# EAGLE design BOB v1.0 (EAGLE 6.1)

## Sheet 1 of 2: Pi Cam Daughterboard

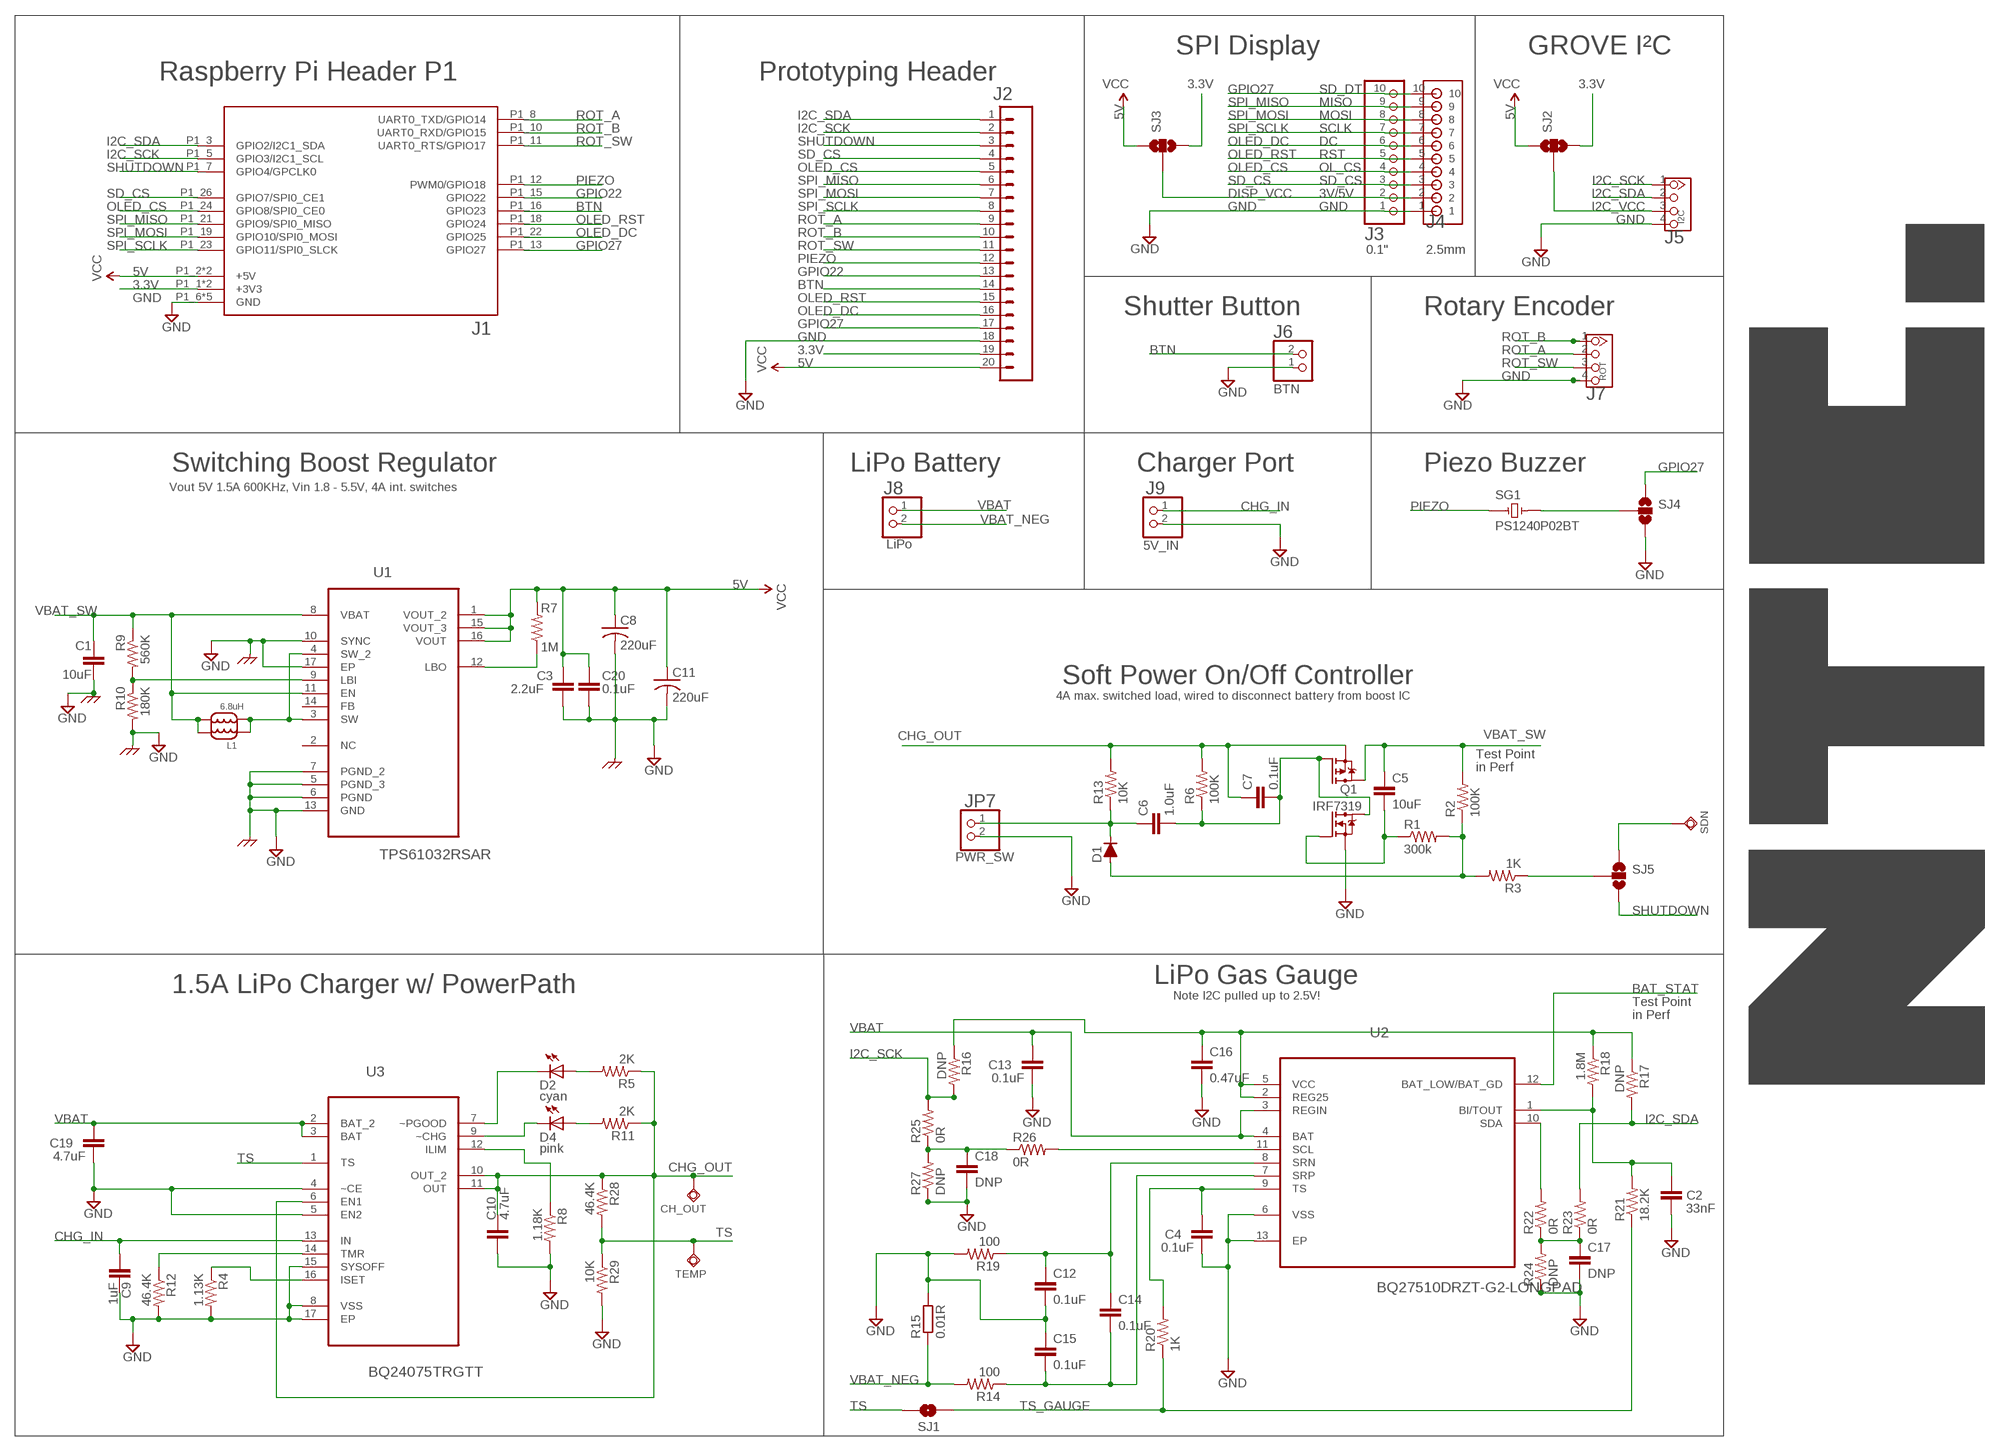
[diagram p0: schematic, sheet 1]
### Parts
C1  10uF  CAP1206  [1206]
C2  33nF  CAP0603-CAP  [0603-CAP]
C3  2.2uF  CAP0603  [0603]
C4  0.1uF  CAP0603-CAP  [0603-CAP]
C5  10uF  10UF-6.3V-20%(0603)  [0603-CAP]
C6  1.0uF  1.0UF-16V-10%(0603)  [0603-CAP]
C7  0.1uF  0.1UF-25V-5%(0603)  [0603-CAP]
C8  220uF  C-USC1210  [C1210]
C9  1uF  CAP0603-CAP  [0603-CAP]
C10  4.7uF  CAP0603-CAP  [0603-CAP]
C11  220uF  C-USC1210  [C1210]
C12  0.1uF  CAP0603-CAP  [0603-CAP]
C13  0.1uF  CAP0603-CAP  [0603-CAP]
C14  0.1uF  CAP0603-CAP  [0603-CAP]
C15  0.1uF  CAP0603-CAP  [0603-CAP]
C16  0.47uF  CAP0603-CAP  [0603-CAP]
C17  DNP  CAP0603-CAP  [0603-CAP]
C18  DNP  CAP0603-CAP  [0603-CAP]
C19  4.7uF  CAP0603-CAP  [0603-CAP]
C20  0.1uF  1.0UF-16V-10%(0603)  [0603-CAP]
CH_OUT  TP1.2  [TP_1.2]
D1  D-FILL-SMB  [SMB]
D2  cyan  LED0603  [LED-0603]
D4  pink  LED0603  [LED-0603]
J1  PICAM_RPI-B-PICAM  [PICAM_RPI-B-PICAM]
J2  M20LOCK_LONGPADS  [1X20_LOCK_LONGPADS]
J3  PINHD-1X10  [1X10-BIG]
J4  B10B-EH-A-RA  [S10B-EH]
J5  I2C  TWIG-4P-2.0-2.0  [4P-2.0]
J6  BTN  PICAM_JST_2PIN-THM  [PICAM_JST-PH-2-THM]
J7  ROT  TWIG-4P-2.0-2.0  [4P-2.0]
J8  LiPo  PICAM_JST_2PIN-THM  [PICAM_JST-PH-2-THM]
J9  5V_IN  PICAM_JST_2PIN-THM  [PICAM_JST-PH-2-THM]
JP7  PWR_SW  PICAM_JST_2PIN-THM  [PICAM_JST-PH-2-THM]
L1  6.8uH  SUMIDA_CDRH124CDRH124NP-6R8MC  [SUMIDA_CDRH124]
Q1  IRF7319  IRF7319Q  [SO08-IRF]
R1  300k  RESISTOR0603-RES  [0603-RES]
R2  100K  RESISTOR0603-RES  [0603-RES]
R3  1K  RESISTOR0603-RES  [0603-RES]
R4  1.13K  RESISTOR0603-RES  [0603-RES]
R5  2K  RESISTOR0603-RES  [0603-RES]
R6  100K  RESISTOR0603-RES  [0603-RES]
R7  1M  RESISTOR0603-RES  [0603-RES]
R8  1.18K  RESISTOR0603-RES  [0603-RES]
R9  560K  RESISTOR0603-RES  [0603-RES]
R10  180K  RESISTOR0603-RES  [0603-RES]
R11  2K  RESISTOR0603-RES  [0603-RES]
R12  46.4K  RESISTOR0603-RES  [0603-RES]
R13  10K  RESISTOR0603-RES  [0603-RES]
R14  100  RESISTOR0603-RES  [0603-RES]
R15  0.01R  RESISTOR-1206  [R1206]
R16  DNP  RESISTOR0603-RES  [0603-RES]
R17  DNP  RESISTOR0603-RES  [0603-RES]
R18  1.8M  RESISTOR0603-RES  [0603-RES]
R19  100  RESISTOR0603-RES  [0603-RES]
R20  1K  RESISTOR0603-RES  [0603-RES]
R21  18.2K  RESISTOR0603-RES  [0603-RES]
R22  0R  RESISTOR0603-RES  [0603-RES]
R23  0R  RESISTOR0603-RES  [0603-RES]
R24  DNP  RESISTOR0603-RES  [0603-RES]
R25  0R  RESISTOR0603-RES  [0603-RES]
R26  0R  RESISTOR0603-RES  [0603-RES]
R27  DNP  RESISTOR0603-RES  [0603-RES]
R28  46.4K  RESISTOR0603-RES  [0603-RES]
R29  10K  RESISTOR0603-RES  [0603-RES]
SDN  TP1.2  [TP_1.2]
SG1  PS1240P02BT  [PS1240]
SJ1  SOLDERJUMPER-OLDTRACE  [SJ_2S-TRACE]
SJ2  SOLDERJUMPER_2WAYPASTE1&2  [SJ_3_PASTE1&2]
SJ3  SOLDERJUMPER_2WAYPASTE2&3  [SJ_3_PASTE2&3]
SJ4  SOLDERJUMPER_2WAYPASTE1&2  [SJ_3_PASTE1&2]
SJ5  SOLDERJUMPER_2WAYPASTE2&3  [SJ_3_PASTE2&3]
TEMP  TP1.2  [TP_1.2]
U1  TPS61032RSAR  [QFN65P400X400X100-17N]
U2  BQ27510DRZT-G2-LONGPAD  [SON40P400X250X100-13N+LONGPAD]
U3  BQ24075TRGTT  [QFN50P300X300X100-17N]

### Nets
3.3V: J1.P1_1(+3V3) J1.P1_17(+3V3) J2.19 SJ2.3 SJ3.3
5V: C3.1 C8.1 C11.1 C20.1 J1.P1_2(+5V) J1.P1_4(+5V) J2.20 R7.2 SJ2.1 SJ3.1 U1.1(VOUT_2) U1.15(VOUT_3) U1.16(VOUT) ; supply symbol labelled VCC
BAT_STAT: U2.12(BAT_LOW/BAT_GD)
BTN: J1.P1_16(GPIO23) J2.14 J6.2
CHG_IN: C9.1 J9.1 U3.13(IN)
CHG_OUT: C7.1 C10.1 CH_OUT.1(TP) Q1.3(P-S2) R5.1 R6.2 R11.1 R13.2 R28.1 U3.6(EN1) U3.10(OUT_2) U3.11(OUT)
DISP_VCC: J3.2 J4.2 SJ3.2
GND: C1.2 C2.2 C3.2 C4.2 C8.2 C9.2 C10.2 C11.2 C12.2 C13.2 C15.1 C16.2 C17.2 C18.2 C19.2 C20.2 J1.P1_6(GND) J1.P1_9(GND) J1.P1_14(GND) J1.P1_20(GND) J1.P1_25(GND) J2.18 J3.1 J4.1 J5.4 J6.1 J7.4 J9.2 JP7.2 Q1.1(N-S1) R4.2 R8.2 R10.2 R12.2 R15.2 R19.2 R24.1 R27.1 R29.2 SJ4.3 U1.5(PGND_3) U1.6(PGND) U1.7(PGND_2) U1.10(SYNC) U1.13(GND) U1.17(EP) U2.6(VSS) U2.13(EP) U3.4(~CE) U3.5(EN2) U3.8(VSS) U3.15(SYSOFF) U3.17(EP)
GPIO22: J1.P1_15(GPIO22) J2.13
GPIO27: J1.P1_13(GPIO27) J2.17 J3.10 J4.10 SJ4.1
I2C_SCK: J1.P1_5(GPIO3/I2C1_SCL) J2.2 J5.1 R16.2 R25.2
I2C_SDA: J1.P1_3(GPIO2/I2C1_SDA) J2.1 J5.2 R17.2 R23.2
I2C_VCC: J5.3 SJ2.2
L1: L1.P$3 L1.P$4 U1.3(SW) U1.4(SW_2)
N$1: C6.1 D1.1(C) JP7.1 R13.1
N$2: C2.1 R18.2 R21.2 U2.1(BI/TOUT)
N$4: C17.1 R22.1 R23.1 R24.2
N$5: D4.C U3.9(~CHG)
N$6: R7.1 U1.12(LBO)
N$7: R9.2 R10.1 U1.9(LBI)
N$8: R12.1 U3.14(TMR)
N$9: C5.2 Q1.2(N-G1) R1.1
N$10: R4.1 U3.16(ISET)
N$11: D4.A R11.2
N$12: D2.C U3.7(~PGOOD)
N$13: D2.A R5.2
N$14: C6.2 C7.2 Q1.4(P-G2) Q1.7(N-D1) Q1.8(N-D1) R6.1
N$15: D1.2(A) R1.2 R2.1 R3.2
N$16: R22.2 U2.10(SDA)
N$17: C18.1 R25.1 R26.1 R27.2
N$19: R8.1 U3.12(ILIM)
N$20: R26.2 U2.11(SCL)
N$21: C4.1 R20.2 U2.9(TS)
N$23: SG1.P$2 SJ4.2
N$24: C16.1 R16.1 R17.1 R18.1 U2.2(REG25) U2.5(VCC)
N$29: R3.1 SJ5.2
N$34: SDN.1(TP) SJ5.1
OLED_CS: J1.P1_24(GPIO8/SPI0_CE0) J2.5 J3.4 J4.4
OLED_DC: J1.P1_22(GPIO25) J2.16 J3.6 J4.6
OLED_RST: J1.P1_18(GPIO24) J2.15 J3.5 J4.5
PIEZO: J1.P1_12(PWM0/GPIO18) J2.12 SG1.P$1
ROT_A: J1.P1_8(UART0_TXD/GPIO14) J2.9 J7.2
ROT_B: J1.P1_10(UART0_RXD/GPIO15) J2.10 J7.1
ROT_SW: J1.P1_11(UART0_RTS/GPIO17) J2.11 J7.3
SD_CS: J1.P1_26(GPIO7/SPI0_CE1) J2.4 J3.3 J4.3
SHUTDOWN: J1.P1_7(GPIO4/GPCLK0) J2.3 SJ5.3
SPI_MISO: J1.P1_21(GPIO9/SPI0_MISO) J2.6 J3.9 J4.9
SPI_MOSI: J1.P1_19(GPIO10/SPI0_MOSI) J2.7 J3.8 J4.8
SPI_SCLK: J1.P1_23(GPIO11/SPI0_SLCK) J2.8 J3.7 J4.7
SRN: C12.1 C14.1 R19.1 U2.8(SRN)
SRP: C14.2 C15.2 R14.1 U2.7(SRP)
TS: R28.2 R29.1 SJ1.1 TEMP.1(TP) U3.1(TS)
TS_GAUGE: R20.1 R21.1 SJ1.2
VBAT: C13.1 C19.1 J8.1 U2.3(REGIN) U2.4(BAT) U3.2(BAT_2) U3.3(BAT)
VBAT_NEG: J8.2 R14.2 R15.1
VBAT_SW: C1.1 C5.1 L1.P$1 L1.P$2 Q1.5(P-D2) Q1.6(P-D2) R2.2 R9.1 U1.8(VBAT) U1.11(EN)
Unconnected: U1.2(NC) U1.14(FB)

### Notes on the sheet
- SPI Display | GROVE I²C
- Raspberry Pi Header P1 | Prototyping Header
- SD_DT
- MISO
- MOSI
- SCLK
- DC
- RST
- OL_CS
- SD_CS
- 3V/5V
- GND
- 0.1" | 2.5mm
- Shutter Button | Rotary Encoder
- J1
- Switching Boost Regulator | LiPo Battery | Charger Port | Piezo Buzzer
- Vout 5V 1.5A 600KHz, Vin 1.8 - 5.5V, 4A int. switches
- Soft Power On/Off Controller
- 4A max. switched load, wired to disconnect battery from boost IC
- Test Point
- in Perf
- LiPo Gas Gauge
- 1.5A LiPo Charger w/ PowerPath
- Note I2C pulled up to 2.5V!
- Test Point
- in Perf

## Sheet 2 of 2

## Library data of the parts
C1 C3 = CH_passive:CAP: Capacitor
C2 C4 C9 C10 C13 C19 = SparkFun:CAP: Capacitor
C5 = SparkFun-Capacitors:10UF-6.3V-20%(0603): CAP-11015; PROD_ID: CAP-11015
C6 = SparkFun-Capacitors:1.0UF-16V-10%(0603): CAP-00868; PROD_ID: CAP-00868
C7 = SparkFun-Capacitors:0.1UF-25V-5%(0603): CAP-08604; PROD_ID: CAP-08604
C8 C11 = adafruit:C-US: CAPACITOR, American symbol
C12 C14-C18 = SparkFun-Capacitors:CAP: Capacitor
C20 = SparkFun-Capacitors:1.0UF-16V-10%(0603): CAP-00868; PROD_ID: CAP-00868; VALUE: 1.0uF
CH_OUT SDN TEMP = TESTPAD:TP: Testpad hole 0.8mm (32mil)
D1 = semicon-smd-ipc:D-FILL-: DIODE
D2 D4 = SparkFun:LED: LEDs
J1 = PiCam_V0.5:PICAM_RPI-B-PICAM: Second revision of the Model 2 board including the P5 and P6 headers. Mounting holes have been added. Choose the "SHIELD" variant for a predefined Dimension layer and drilling holes. Theres also a "SHIELD" variant for the Model A without a RJ45 connector.
J2 = SparkFun-Connectors:M20: 1x20 .1" header This is just like the LOCK variant in that the holes are staggared by 5 mil, but except for the last two holes. They are not altered from the "standard" footprint layout. This is used for a special purpose on the layout of our Graphic LCD Backpack. Make sure you want to use this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
J3 = adafruit:PINHD-1X10: Pin header 1x10 0.1" spacing With round pins
J4 = jst:B10B-EH-A
J5 J7 = Connector :TWIG-4P-2.0
J6 J8 J9 JP7 = PiCam_V0.5:PICAM_JST_2PIN: JST 2-Pin Connectors of various flavors
L1 = PiCam_V0.5:SUMIDA_CDRH124: Sumida CDRH124-xx SMD Power Inductor 12.3 x 12.3 x 4.5mm Max. RoHS Compliant Magnetically Shielded Ferrite Drum Core; INDUCTANCE: 6.8uH
Q1 = PiCam:IRF7319
R1-R3 R6 R13 = SparkFun-Passives:RESISTOR: Resistor
R4 R5 R7-R12 R14 R16-R19 R28 R29 = SparkFun:RESISTOR: Resistor
R15 = dp_devices.v6:RESISTOR; PRECISION: 1%; WATT: 1/4W
R20-R27 = SparkFun-Resistors:RESISTOR: Resistor; PRECISION: 1%; WATT: 1/4W
SG1 = TDK-U:PS1240P02BT: Buzzer 70dB/3V
SJ1 = SparkFun-Passives:SOLDERJUMPER-OLD: Solder Jumper
SJ2-SJ5 = SparkFun-Passives:SOLDERJUMPER_2WAY: Solder Jumper 2 way solder jumper
U1 = Texas Instruments_By_element14_Batch_1:TPS61032RSAR: SYNCHRONOUS BOOST CONVERTER; MPN: TPS61032RSAR; OC_FARNELL: 1743713; OC_NEWARK: 90H4861; PACKAGE: QFN-16; SUPPLIER: Texas Instruments
U2 = Texas Instruments_By_element14_Batch_1:BQ27510DRZT-G2: System-Side Impedance Track Fuel Gauge; MPN: BQ27510DRZT-G2; SUPPLIER: Texas Inustruments
U3 = Texas Instruments_By_element14_Batch_1:BQ24075TRGTT: 1.5A USB-Friendly Li-Ion Battery Charger and Power-Path Management IC; MPN: BQ24075TRGTT; OC_FARNELL: -; OC_NEWARK: 63R9856; PACKAGE: QFN-16; SUPPLIER: Texas Instruments

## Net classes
0 default: width 0.254 mm

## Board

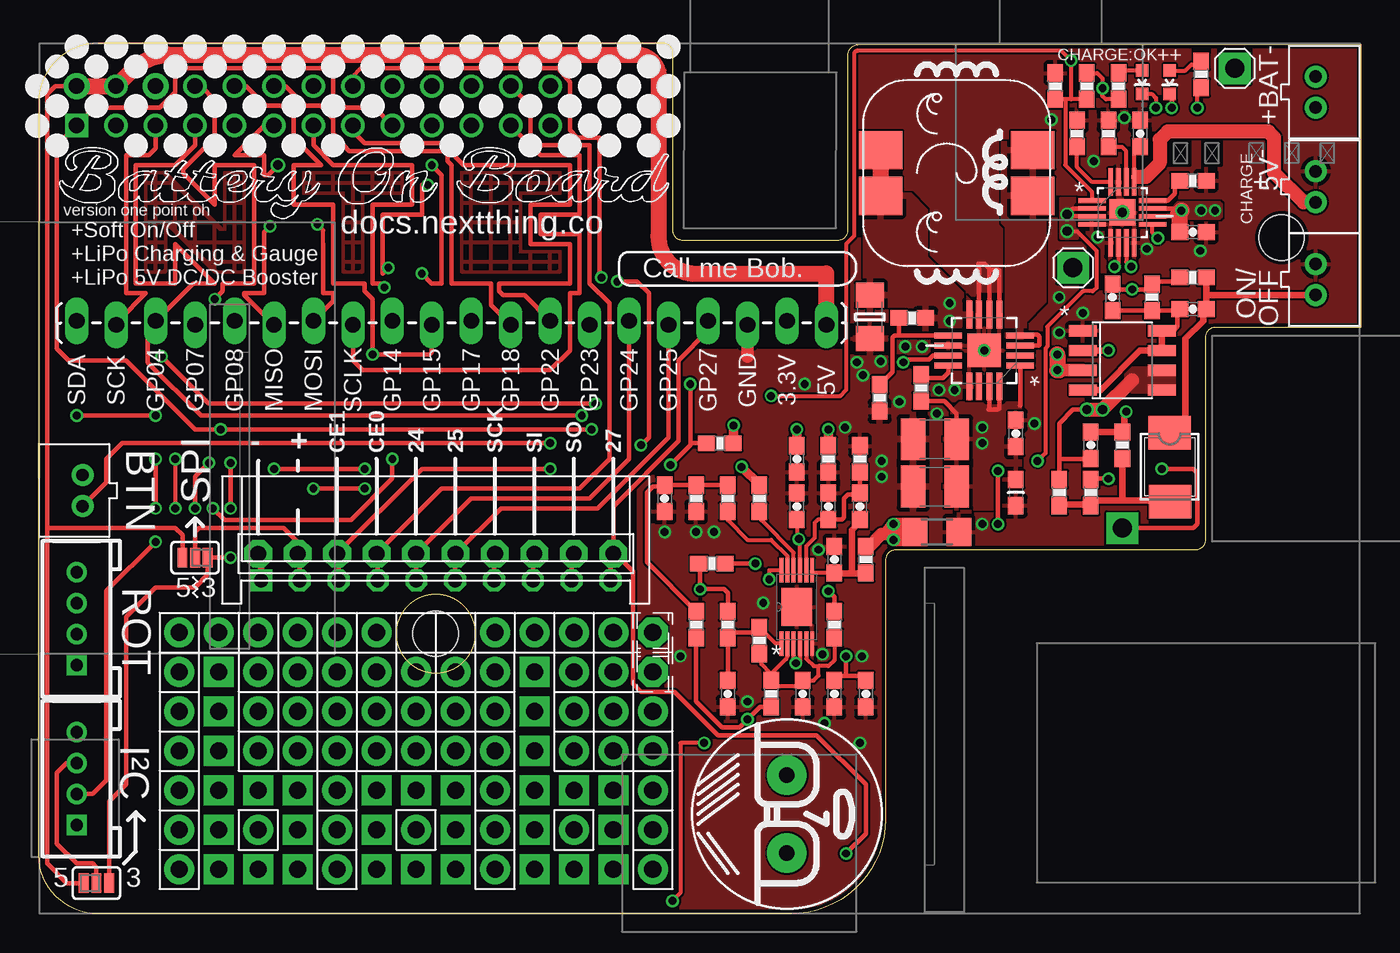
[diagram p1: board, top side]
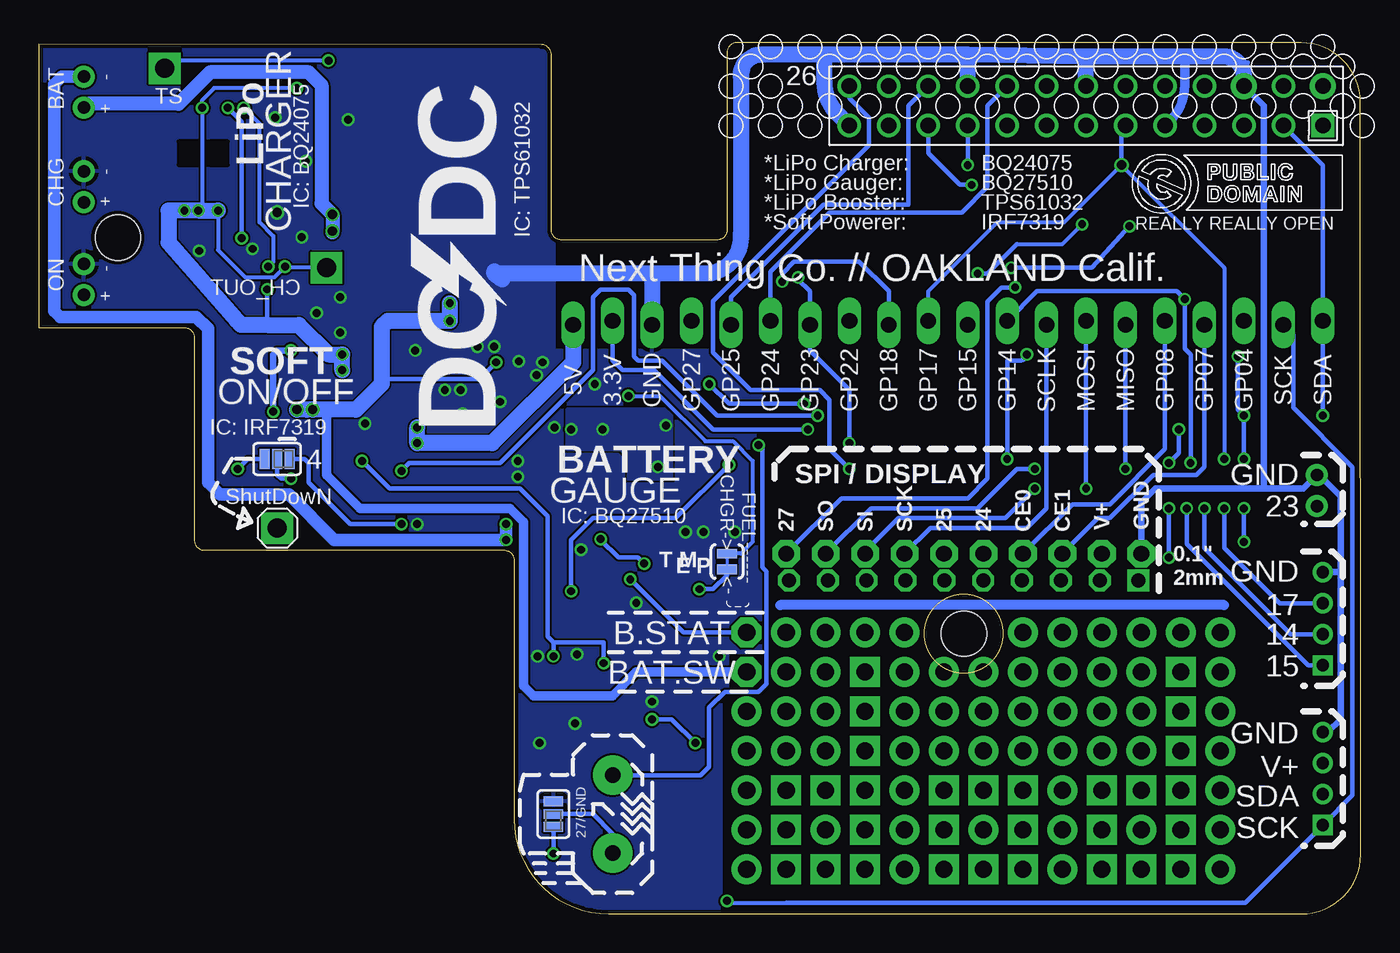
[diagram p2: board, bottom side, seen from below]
Size 85.09 x 56.08 mm. Coordinates in mm from the lower left corner, seen from the top.
Outline: circle at 25.55,18.03 radius 2.54
Copper layers (1*16): Top 0.035mm / dielectric 1.5mm / Bottom 0.035mm
Design rules: minimum track width 5mil, minimum drill 12mil, track to track 5mil, track to pad 5mil, pad to pad 5mil, via to via 5mil, smd to smd 0mil, copper to edge 10mil, drill to drill 10mil, minimum pad ring 10mil, minimum via ring 6mil, stop-mask expansion 2mil, vias tented up to drill 25mil, thermal gap 10mil
tKeepout: area 7.8,1.5 to 40.9,19.5
bKeepout: area 7.8,1.5 to 40.9,19.5
tRestrict: area 72.9,48.2 to 74.1,49.7; area 75,48.2 to 76.1,49.7; area 7.8,1.5 to 40.9,19.5; area 60.5,38 to 61.9,39.8
bRestrict: area 72.9,48.2 to 74.1,49.7; area 75,48.2 to 76.1,49.7; area 7.8,1.5 to 40.9,19.5
vRestrict: area 7.8,1.5 to 40.9,19.5

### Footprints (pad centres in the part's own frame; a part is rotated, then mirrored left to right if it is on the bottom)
1206 = smd 1.6 x 1.8: 1 -1.4,0; 2 1.4,0
0603-CAP = smd 1.1 x 1: 1 -0.85,0; 2 0.85,0
0603 = smd 1.1 x 1: 1 -0.85,0; 2 0.85,0
C1210 = smd 1.6 x 2.7: 1 -1.4,0; 2 1.4,0
SPARKFUN-CAPACITORS_0603-CAP = smd 1.1 x 1: 1 -0.85,0; 2 0.85,0
TP_1.2 = drill 1.219 pad 2.032 square: 1 0,0
SMB = smd 2.159 x 2.743: 1 -2.311,-0.127; 2 2.108,-0.102
SPARKFUN_LED-0603 = smd 0.8 x 0.8: A 0,-0.75; C 0,0.75
LED-0603 = smd 0.8 x 0.8: A 0,-0.75; C 0,0.75
PICAM_RPI-B-PICAM = drill 1 square: P1_1 -36.83,20.32 | drill 1 pad 1.676: P1_2 -36.83,22.86; P1_6 -31.75,22.86 | drill 1: P1_3 -34.29,20.32; P1_4 -34.29,22.86; P1_5 -31.75,20.32; P1_7 -29.21,20.32; P1_8 -29.21,22.86; P1_9 -26.67,20.32; P1_10 -26.67,22.86; P1_11 -24.13,20.32; P1_12 -24.13,22.86; P1_13 -21.59,20.32; P1_14 -21.59,22.86; P1_15 -19.05,20.32; P1_16 -19.05,22.86; P1_17 -16.51,20.32; P1_18 -16.51,22.86; P1_19 -13.97,20.32; P1_20 -13.97,22.86; P1_21 -11.43,20.32; P1_22 -11.43,22.86; P1_23 -8.89,20.32; P1_24 -8.89,22.86; P1_25 -6.35,20.32; P1_26 -6.35,22.86 | hole 2.9: -13.73,-12.4; 40.74,13.11
1X20_LOCK_LONGPADS = drill 1.016 long: 1 0,0.127; 2 2.54,-0.127; 3 5.08,0.127; 4 7.62,-0.127; 5 10.16,0.127; 6 12.7,-0.127; 7 15.24,0.127; 8 17.78,-0.127; 9 20.32,0.127; 10 22.86,-0.127; 11 25.4,0.127; 12 27.94,-0.127; 13 30.48,0.127; 14 33.02,-0.127; 15 35.56,0.127; 16 38.1,-0.127; 17 40.64,0.127; 18 43.18,-0.127; 19 45.72,0.127; 20 48.26,-0.127
1X10-BIG = drill 1.016 pad 1.778 octagon: 1 -11.43,0; 2 -8.89,0; 3 -6.35,0; 4 -3.81,0; 5 -1.27,0; 6 1.27,0; 7 3.81,0; 8 6.35,0; 9 8.89,0; 10 11.43,0
S10B-EH = drill 0.9 square: 1 -11.25,0 | drill 0.9 octagon: 2 -8.75,0; 3 -6.25,0; 4 -3.75,0; 5 -1.25,0; 6 1.25,0; 7 3.75,0; 8 6.25,0; 9 8.75,0; 10 11.25,0
4P-2.0 = drill 0.8 pad 1.27 square: 1 -3,0 | drill 0.8 pad 1.27: 2 -1,0; 3 1,0; 4 3,0
PICAM_JST-PH-2-THM = drill 0.8 pad 1.422: 1 1,0; 2 -1,0
SUMIDA_CDRH124 = smd 2.45 x 2.8: P$1 -1.475,4.9; P$2 1.475,4.9; P$3 -1.475,-4.9; P$4 1.475,-4.9
SO08-IRF = smd 0.72 x 1.78: 1 -1.905,-2.543; 2 -0.635,-2.543; 3 0.635,-2.543; 4 1.905,-2.543; 5 1.905,2.543; 6 0.635,2.543; 7 -0.635,2.543; 8 -1.905,2.543
0603-RES = smd 1.1 x 1: 1 -0.85,0; 2 0.85,0
R1206 = smd 1.6 x 1.803: 1 -1.422,0; 2 1.422,0
PS12 = drill 1 pad 2.54: P$1 -2.5,0; P$2 2.5,0
SJ_2S-TRACE = smd 0.635 x 1.27: 1 -0.508,0; 2 0.508,0
SJ_3_PASTE1&2 = smd 0.635 x 1.27: 1 -0.813,0; 2 0,0; 3 0.813,0
SJ_3_PASTE2&3 = smd 0.635 x 1.27: 1 -0.813,0; 2 0,0; 3 0.813,0
QFN65P400X400X100-17N = smd 1.778 x 0.381: 1 -2.311,0.965; 2 -2.311,0.33; 3 -2.311,-0.33; 4 -2.311,-0.965; 9 2.311,-0.965; 10 2.311,-0.33; 11 2.311,0.33; 12 2.311,0.965 | smd 0.381 x 1.778: 5 -0.965,-2.311; 6 -0.33,-2.311; 7 0.33,-2.311; 8 0.965,-2.311; 13 0.965,2.311; 14 0.33,2.311; 15 -0.33,2.311; 16 -0.965,2.311 | smd 2.159 x 2.159: 17 0,0
SON40P400X250X100-13N+LONGPAD = smd 1.575 x 0.254: 1 -2.362,0.991; 2 -2.362,0.61; 3 -2.362,0.203; 4 -2.362,-0.203; 5 -2.362,-0.61; 6 -2.362,-0.991; 7 2.362,-0.991; 8 2.362,-0.61; 9 2.362,-0.203; 10 2.362,0.203; 11 2.362,0.61; 12 2.362,0.991 | smd 2.438 x 1.956: 13 0,0
QFN50P300X300X100-17N = smd 1.778 x 0.305: 1 -1.956,0.762; 2 -1.956,0.254; 3 -1.956,-0.254; 4 -1.956,-0.762; 9 1.956,-0.762; 10 1.956,-0.254; 11 1.956,0.254; 12 1.956,0.762 | smd 0.305 x 1.778: 5 -0.762,-1.956; 6 -0.254,-1.956; 7 0.254,-1.956; 8 0.762,-1.956; 13 0.762,1.956; 14 0.254,1.956; 15 -0.254,1.956; 16 -0.762,1.956 | smd 1.702 x 1.702: 17 0,0

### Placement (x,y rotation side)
C1  53.49,38.43 270 top
C2  44.35,14.17 270 top
C3  62.89,27.13 270 top
C4  48.79,26.24 90 top
C5  67.71,30.18 90 top
C6  74.29,38.94 180 top
C7  69.11,39.7 270 top
C8  57.68,27.51 180 top
C9  70.89,50.24 90 top
C10  74.29,43.89 0 top
C11  57.68,30.56 180 top
C12  0.1uF  [SPARKFUN-CAPACITORS_0603-CAP]  50.82,26.24 90 top
C13  0.1uF  [SPARKFUN-CAPACITORS_0603-CAP]  53.24,14.17 270 top
C14  0.1uF  [SPARKFUN-CAPACITORS_0603-CAP]  52.86,26.24 270 top
C15  0.1uF  [SPARKFUN-CAPACITORS_0603-CAP]  51.2,22.81 270 top
C16  0.47uF  [SPARKFUN-CAPACITORS_0603-CAP]  49.17,14.17 270 top
C17  DNP  [SPARKFUN-CAPACITORS_0603-CAP]  48.79,29.29 270 top
C18  DNP  [SPARKFUN-CAPACITORS_0603-CAP]  40.28,26.75 270 top
C19  51.2,14.17 270 top
C20  62.89,30.94 90 top
CH_OUT  66.57,41.61 0 top
D1  72.92,28.65 270 top
D2  cyan  [SPARKFUN_LED-0603]  71.02,53.54 180 top
D4  72.79,53.54 180 top
J1  39.27,30.43 0 top
J2  2.44,38.05 0 top
J3  25.55,23.19 0 top
J4  25.55,21.48 0 top
J5  2.44,8.71 90 top
J6  2.82,27.25 90 top
J7  2.44,19 90 top
J8  82.19,52.91 270 top
J9  82.19,46.81 270 top
JP7  82.19,40.84 270 top
L1  59.08,47.7 90 top
Q1  69.75,35.64 270 top
R1  69.75,30.18 270 top
R2  65.68,27.13 90 top
R3  67.71,27.13 270 top
R4  66.83,50.24 90 top
R5  69.49,53.29 90 top
R6  71.65,39.7 90 top
R7  56.79,33.86 270 top
R8  74.29,47.19 0 top
R9  56.22,38.37 180 top
R10  54.13,33.22 270 top
R11  74.83,54.05 90 top
R12  68.86,50.24 90 top
R13  74.29,40.97 180 top
R14  53.24,22.81 90 top
R15  57.81,24.59 0 top
R16  47.14,14.17 270 top
R17  51.2,18.62 90 top
R18  46.38,17.6 90 top
R19  52.86,29.29 90 top
R20  43.33,22.56 0 top
R21  44.35,18.62 270 top
R22  46.38,26.75 270 top
R23  43.84,30.3 180 top
R24  50.82,29.29 90 top
R25  42.31,18.62 270 top
R26  44.35,26.75 270 top
R27  42.31,26.75 90 top
R28  67.46,53.29 270 top
R29  65.43,53.29 90 top
SDN  69.75,24.84 0 bottom
SG1  PS1240P02BT  [PS12]  48.16,6.43 270 top
SJ1  40.79,22.68 270 bottom
SJ2  3.71,1.98 0 top
SJ3  10.06,22.94 0 top
SJ4  51.97,6.43 90 bottom
SJ5  69.75,29.29 0 bottom
TEMP  76.99,54.43 0 top
U1  60.86,36.27 180 top
U2  48.79,19.76 90 top
U3  69.75,45.16 0 top

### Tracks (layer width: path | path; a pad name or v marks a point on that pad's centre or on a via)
3.3V  (via drill 0.51)
  Top 0.305: J1.P1_17 21.61,51.89 19.71,51.89 18.95,52.65 18.95,53.92 18.44,54.43 9.42,54.43 8.79,53.8 8.79,52.91 7.77,51.89 3.58,51.89 J1.P1_1 1.17,49.48 1.17,36.4 1.93,35.64 5.61,35.64 10.06,31.19 v11.71,31.19 v35.58,31.19 | SJ2.3 4.52,7.24 5.61,8.33 5.61,19.13 7.52,21.03 10.06,21.03 10.87,21.84 SJ3.3 v12.34,22.94 | v12.34,26.11 v12.34,29.03
  Bottom 0.279: v35.58,31.19 39.9,31.19
  Bottom 0.305: 39.9,31.19 41.68,31.19 45.49,35 47.52,35 48.16,35.64 J2.19 | v12.34,22.94 v12.34,26.11 | v12.34,29.03 11.71,29.67 v11.71,31.19
5V  (via drill 0.51)
  Top 0.305: R7.2 58.28,33.01 59.08,32.21 C11.1 | 0.53,24.84 0.53,3.25 1.8,1.98 SJ2.1 | 0.53,24.84 0.53,52.78 1.04,53.29 J1.P1_2 | SJ3.1 9.24,24.38 8.79,24.84 0.53,24.84 | U1.1 63.17,32.74 63.14,32.72 | U1.15 61.19,32.54 61.11,32.46 61.75,32.46 61.82,32.54 U1.16
  Top 1.016: J1.P1_2 J1.P1_4 5.79,54.11 arc-45 8.29,55.32 38.47,55.32 arc-90 39.9,53.89 39.9,43.84 arc90 42.01,41.22 50.7,41.22 J2.20
  Bottom 1.016: J2.20 50.7,35.51 55.9,30.3 v60.73,30.3 v60.73,31.32
  pour Top: 59.33,32.84 63.14,32.84 63.14,32.46 62.13,32.46 62.13,30.3 63.14,30.3 63.14,27.76 61.75,27.76 61.75,26.11 58.32,26.11 58.32,31.83
BAT_STAT  (via drill 0.51, 1.1 pad 1.93)
  Top 0.254: U2.12 47.01,22.12 v47.01,21.54
  Bottom 0.305: v47.01,21.54 43.58,18.11 v39.52,18.11
BTN  (via drill 0.5, 0.51)
  Top 0.254: J1.P1_16 20.22,53.92 20.72,54.43 21.49,54.43
  Top 0.279: 21.49,54.43 33.42,54.43 34.19,53.54 34.19,50.45 34.64,49.99 36.09,49.99 36.09,40.97 v36.22,40.97
  Top 0.305: v32.92,30.3 5.36,30.3 4.34,29.29 4.34,27.78 J6.2
  Bottom 0.305: v32.92,30.3 32.92,33.73 35.46,36.27 J2.14 35.46,40.08 36.22,40.84 v36.22,40.97
CHG_IN
  Top 0.254: 70.76,47.45 70.56,47.45 U3.13 70.51,49.01 C9.1
  Top 0.914: 70.76,47.45 71.27,47.45 72.16,48.34 72.16,49.86 72.67,50.37 79.14,50.37 79.53,49.99 79.53,47.7 81.41,45.81 J9.1
CHG_OUT  (via drill 0.51)
  Top 0.254: 69.49,43.64 U3.6 69.49,41.92 v69.24,41.67 | v74.57,51.89 74.57,53.16 74.87,53.16 R11.1 | R28.1 68.13,54.14 68.48,53.8 v68.48,53.16 68.48,52.65 68.69,52.44 R5.1
  Top 0.305: C7.1 69.11,40.91 | U3.11 73.43,45.42 v73.56,45.29 73.18,44.91 U3.10 | R13.2 73.18,40.97 72.92,40.72 71.82,40.72 | 71.82,40.72 R6.2 71.5,40.4 | 69.26,40.4 C7.1 | C7.1 69.45,40.21 v70.38,40.21 71.52,40.21 71.82,40.5 71.82,40.72
  Top 0.813: Q1.3 65.68,35
  Top 1.016: 73.34,45.07 v73.56,45.29 | 65.68,35 v65.56,35 v65.56,36.02 | C10.1 73.45,45.14
  Bottom 0.254: v73.56,45.29 73.56,42.75 71.78,40.97 69.94,40.97 v69.24,41.67 69.18,41.61 CH_OUT.1 | v68.48,53.16 73.81,53.16 74.57,52.4 v74.57,51.89 74.57,45.54 v74.83,45.29
  Bottom 0.305: v70.38,40.21 70.38,37.92
  Bottom 1.016: v65.56,35 v65.56,36.02 66.44,36.02 68.35,37.92 70.38,37.92 72.07,37.92 72.37,38.22 76.73,43.22 76.73,45.29 v74.83,45.29 | 74.7,45.29 v74.83,45.29 | v74.83,45.29 v73.56,45.29
  other vias: 75.72,45.29
  pour Top (no thermals): 72.99,45.42 73.37,45.8 75.97,45.8 76.1,45.67 76.1,44.91 75.97,44.78 73.11,44.78 72.99,44.91
DISP_VCC
  Top 0.305: SJ3.2 10.06,24.59 10.31,24.84 15.77,24.84 16.66,23.95 J3.2 16.8,23.05 J4.2
GND  (via drill 0.51, 0.6)
  Top 0.305: U1.7 60.53,41.81 60.48,41.86 60.86,41.86 61.19,41.53 61.19,41.35 | U1.6 61.19,41.35 | U1.5 61.82,41.4 61.75,41.48 61.31,41.48 61.19,41.35
  Top 0.406: J4.1 14.3,23.01 J3.1
  Top 0.813: J2.18 45.62,35.89
  Bottom 0.254: 7.26,54.81 7.69,54.56
  Bottom 0.406: J5.4 2.1,11.71 1.29,12.52 1.29,22.05 | 1.29,22.05 1.29,26.87 2.67,28.25 J6.1 3.69,27.38 6.25,27.38 | J7.4 1.34,22 1.29,22.05 | J1.P1_6 6.25,52.02 6.25,27.38 | J3.1 14.12,26.49 13.23,27.38 6.25,27.38
  Bottom 0.61: J1.P1_9 12.26,51.09 arc-45 11.33,53.33 11.33,55.19
  Bottom 1.016: J1.P1_6 7.52,53.92 arc-30 7.69,54.56 arc-60 8.79,55.19 11.33,55.19 17.68,55.19 | 17.68,55.19 25.3,55.32 | 25.3,55.32 34.5,55.32 | 34.5,55.32 38.63,55.32 arc-90 39.9,53.92 39.9,43.76 arc90 42.06,41.22 45.62,41.22 | 45.62,41.22 J2.18 | J1.P1_14 17.68,55.19 | J1.P1_20 25.3,55.32 | J1.P1_25 33.65,51.48 arc45 34.5,53.55 34.5,55.32 | 55.27,40.84 55.78,41.22 | 55.78,41.22 55.78,41.35 | 45.62,41.22 55.78,41.22
  other vias: 69.75,45.16 71.33,42.81 65.68,39.7 67.21,38.68 65.68,37.41 74.76,42.68 58.95,33.73 57.94,33.73 60.86,36.27 54.19,35.57 55.4,32.97 52.67,35.51 57.81,32.21 60.73,25.1 65.17,51.13 54.25,28.14 54.25,29.16 49.3,34.11 41.3,16.59 50.57,12.27 52.86,11 50.44,16.71 45.62,13.67 40.28,24.59 43.46,24.59 53.05,34.68 46.63,20.02 52.98,16.59 50.19,23.44 69.87,51.26 42.31,24.59 68.16,43.57 56.86,36.53 55.78,36.53 51.9,31.32 64.1,31.57 67.91,48.46
  pour Top (rank 6): 51.97,55.96 84.99,55.96 84.99,37.8 75.21,37.8 74.95,23.57 54.51,23.57 54.51,0.08 40.79,-0.05 40.79,13.69 39.8,14.68 39.17,14.68 38.63,15.22 38.63,36.27 51.97,36.27
  pour Bottom (rank 6): 51.97,55.96 51.97,36.27 38.63,36.27 38.63,16.84 40.79,16.84 40.79,-0.05 54.51,0.08 54.51,23.57 74.95,23.57 75.21,37.8 84.99,37.8 84.99,55.96
  pour Top: 52.6,37.41 55.01,37.41 55.01,34.37 57.17,32.08 57.17,24.84 54.51,24.84 54.51,30.56 52.6,32.46
  pour Bottom: 59.08,37.41 62.13,37.41 62.13,35.64 61.49,35 57.3,35 56.92,35.38 55.4,35.38 55.4,33.99 56.79,32.59 56.79,31.83 54.38,31.83 52.73,33.48 52.73,37.54 58.95,37.54
GPIO22
  Top 0.279: J2.13 31.27,39.83 29.9,39.83 29.61,40.11 29.61,40.59 34.19,40.59 34.19,43.13 31.65,43.13 31.65,45.67 34.19,45.67 34.19,48.21 27.33,48.21 26.82,48.72 26.82,49.35 26.57,49.61 20.98,49.61 20.22,50.37 J1.P1_15
GPIO27  (via drill 0.5, 0.51)
  Top 0.279: J1.P1_13 17.68,49.48 18.95,48.21 24.03,48.21 24.03,45.67 21.49,45.67 21.49,40.59 21.99,40.59 v22.25,40.34
  Top 0.305: J3.10 37.11,23.19 38.25,22.05 38.25,14.81 38.76,14.3 40.92,14.3 43.71,11.51 50.06,11.51 53.24,8.33 53.24,5.16 v51.97,3.89 | J3.10 36.98,26.24 41.17,30.43 41.17,35.64 43.08,37.54 J2.17 | J4.10 36.8,23.01 J3.10
  Bottom 0.279: v22.25,40.34 23.11,40.34 24.03,39.42 24.03,28.02 25.3,26.75 33.42,26.75 J3.10
  Bottom 0.305: v51.97,3.89 SJ4.1
I2C_SCK  (via drill 0.51)
  Top 0.254: 5.17,38.24 5.23,38.18 J2.2 | v42.82,11 41.3,11 41.3,1.35 v40.79,0.84
  Top 0.279: J1.P1_5 7.52,49.3 7.06,48.84 5.61,48.84 5.61,39.95 6.88,39.95 5.17,38.24 4.98,38.05
  Top 0.305: R25.2 42.31,13.67 43.97,12.01 45.11,12.01 v45.62,12.52 46.42,13.32 R16.2
  Bottom 0.254: v40.79,0.84 40.66,0.71 36.98,0.71
  Bottom 0.279: 9.42,0.71 36.98,0.71 | v45.62,12.52 44.35,12.52 v42.82,11
  Bottom 0.305: J2.2 4.34,37.29 4.34,32.59 0.53,28.78 0.53,7.62 J5.1 7.44,0.71 9.42,0.71
I2C_SDA  (via drill 0.51)
  Top 0.305: v35.84,32.84 10.95,32.84 v7.9,35.89 | v2.44,32.08 v7.52,32.08 | R17.2 51.2,20.4 v50.82,20.78 | v41.93,34.11 41.93,30.3 | R23.2 41.93,30.3 | J5.2 3.47,7.71 4.34,8.59 4.34,20.78 v7.52,23.95 | v7.52,26.11 v7.52,29.29 | 41.93,30.3 41.93,30.18 v40.66,28.91
  Bottom 0.305: v2.44,32.08 J2.1 2.44,48.21 J1.P1_3 | v7.9,35.89 7.9,32.46 v7.52,32.08 v7.52,29.29 | v40.66,28.91 44.09,25.48 49.43,25.48 50.82,24.08 v50.82,20.78 | v35.84,32.84 40.66,32.84 v41.93,34.11 | v7.52,23.95 v7.52,26.11
I2C_VCC
  Top 0.305: J5.3 1.79,9.71 1.17,9.09 1.17,4.52 2.44,3.25 3.45,3.25 3.71,3 SJ2.2
L1
  Top 0.305: 63.6,36.6 U1.3 64.36,36.6 64.41,36.65 64.41,37.16 64.29,37.29 63.22,37.29 U1.4 63.6,37.24
  pour Top: 62.13,49.61 64.67,49.61 64.67,39.45 63.4,38.18 63.4,37.16 62.38,37.16 62.38,44.27 62.13,44.53
N$1
  Top 0.406: D1.1 73.45,30.96 73.81,31.32 73.81,37.03 74.95,38.18 74.95,38.85 C6.1 75.14,39.95 | 75.04,40.75 R13.1 75.14,39.95 | JP7.1 75.15,39.84 75.14,39.95
N$2
  Top 0.254: U2.1 47.43,17.4 R18.2
  Top 0.305: 46.38,18.49 R18.2 46.04,18.11 44.35,18.11 R21.2 C2.1
N$4  (via drill 0.51)
  Top 0.61: R24.2 v50.82,31.19 | C17.1 v48.79,31.19 | v44.73,31.45 44.73,30.34 R23.1 | R22.1 46.38,27.64 v45.24,28.78
  pour Bottom: 44.35,28.02 44.35,32.46 51.08,32.46 51.08,29.92 47.65,29.92 47.14,29.41 47.14,28.02
N$5  (via drill 0.51)
  Top 0.254: U3.9 71.65,44.4 71.65,43.89 v72.03,43.51
  Top 0.305: v72.92,51.89 72.92,52.67 D4.C
  Bottom 0.305: v72.03,43.51 72.03,51 v72.92,51.89
N$6
  Top 0.305: R7.1 57.01,34.49 58.19,34.49 58.55,34.85 U1.12
N$7
  Top 0.305: U1.9 55.33,37.24 | 55.33,37.24 55.09,37.24 54.95,37.1 54.95,34.9 R10.1 | R9.2 55.37,37.28 55.33,37.24
N$8
  Top 0.254: U3.14 70,49.1 69.71,49.39 R12.1
N$9  (via drill 0.51)
  Top 0.406: 68.69,31.03 C5.2 R1.1 69.87,31.15 69.87,32.21 v70,32.33 | v68.86,36.27 Q1.2
  Bottom 0.406: v68.86,36.27 69.75,36.27 70,36.02 v70,32.33
N$10
  Top 0.254: R4.1 66.83,48.08 67.79,47.12 U3.16
N$11
  Top 0.254: D4.A 73.8,54.29 74.19,54.69 74.61,54.69 R11.2
N$12  (via drill 0.51)
  Top 0.254: D2.C 71.64,52.79 71.91,52.53 v71.91,51.89 | U3.7 70,41.99 v70.32,41.67
  Bottom 0.254: v71.91,51.89 70.89,50.88 70.89,44.53 70,43.64 70,41.99 v70.32,41.67
N$13
  Top 0.254: D2.A 69.77,54.29 R5.2
N$14
  Top 0.305: C7.2 R6.1 73.25,38.85 C6.2 | C6.2 73.3,38.94 | Q1.8 73.05,37.54 73.3,37.8 73.3,38.9 C6.2
  Top 0.406: Q1.8 Q1.7 70.89,36.27 68.35,33.73 Q1.4
N$15
  Top 0.406: 72.92,26.44 D1.2 72.74,26.62 69.75,26.62 | R1.2 69.75,26.62 | R2.1 65.77,26.37 67.71,26.37 R3.2 67.8,26.37 67.8,26.45 67.84,26.49 67.84,26.62 69.75,26.62
N$16
  Top 0.254: U2.10 48.59,23.26 46.51,25.35 R22.2
N$17
  Top 0.305: R26.1 R27.2 C18.1 40.19,27.51 39.52,27.51 39.14,27.13 39.14,22.64 R25.1
N$18  (via drill 1.1 pad 1.93)
  other vias: 39.52,10.49
N$19
  Top 0.305: U3.12 72.67,45.92 73.11,46.37 73.11,46.94 73.24,47.07 73.56,47.07 73.43,47.19 R8.1
N$20
  Top 0.254: 48.18,22.28 U2.11 48.18,23.03 47.14,24.08 45.62,24.08 44.35,25.35 R26.2
N$21  (via drill 0.51)
  Top 0.254: C4.1 48.79,24.26 v48.92,24.13 48.99,24.05 U2.9
  Top 0.305: R20.2 v46.12,22.56
  Bottom 0.254: 48.92,24.08 v48.92,24.13
  Bottom 0.305: 48.92,24.08 47.78,22.94 46.51,22.94 v46.12,22.56
N$22  (via drill 1.1 pad 1.93)
  other vias: 39.52,7.95
N$23
  Bottom 0.305: SJ4.2 49.43,6.43 48.16,5.16 SG1.P$2
N$24
  Top 0.254: 48.18,17.12 U2.2 48.18,16.6 48.1,16.4 47.14,15.44 | 46.42,16.71 R18.1 46.51,16.63 46.51,16.08 47.14,15.44 | 49.4,17.25 U2.5 49.4,16.43 49.88,15.95 50.19,15.95 | 49.26,15.32 C16.1 | C16.1 49.08,14.68 47.14,14.68 R16.1 47.14,15.44 | R17.1 51.2,16.33 50.82,15.95 50.19,15.95 | C16.1 49.87,15.02 50.19,15.34 50.19,15.95
N$25  (via drill 1.1 pad 1.93)
  other vias: 39.52,5.41
N$26  (via drill 1.1 pad 1.93)
  other vias: 39.52,2.87
N$27  (via drill 1.1 pad 1.93)
  other vias: 19.2,10.49
N$28  (via drill 1.1 pad 1.93)
  other vias: 39.52,13.03
N$29  (via drill 0.51)
  Top 0.305: R3.1 67.8,27.98 67.84,28.02 v68.86,28.02
  Bottom 0.305: v68.86,28.02 69.49,28.02 69.75,28.27 SJ5.2
N$30
  pour Top (hatched): 6.88,47.7 6.88,41.35 8.15,41.35 8.15,44.53 11.33,41.35 13.23,41.35 13.23,47.7 11.96,47.7 11.96,43.89 8.15,47.7
N$31
  pour Top (hatched): 17.04,47.7 17.04,46.43 19.58,46.43 19.58,41.35 20.85,41.35 20.85,46.43 23.39,46.43 23.39,47.7
N$32
  pour Top (hatched): 27.2,47.7 27.2,41.35 33.55,41.35 33.55,42.62 31.01,42.62 31.01,46.43 33.55,46.43 33.55,47.7
N$33  (via drill 1.1 pad 1.93)
  other vias: 9.04,18.11
N$34  (via drill 0.51)
  Top 0.305: v72.29,28.65 74.32,28.65 74.57,28.4 74.57,25.1 74.32,24.84 SDN.1
  Bottom 0.305: SJ5.1 71.65,29.29 v72.29,28.65
N$35  (via drill 1.1 pad 1.93)
  other vias: 11.58,15.57
N$36  (via drill 1.1 pad 1.93)
  other vias: 11.58,13.03
N$37  (via drill 1.1 pad 1.93)
  other vias: 11.58,10.49
N$38  (via drill 1.1 pad 1.93)
  other vias: 11.58,7.95
N$39  (via drill 1.1 pad 1.93)
  other vias: 11.58,5.41
N$40  (via drill 1.1 pad 1.93)
  other vias: 11.58,2.87
N$41  (via drill 1.1 pad 1.93)
  other vias: 11.58,18.11
N$42  (via drill 1.1 pad 1.93)
  other vias: 9.04,15.57
N$43  (via drill 1.1 pad 1.93)
  other vias: 9.04,13.03
N$44  (via drill 1.1 pad 1.93)
  other vias: 9.04,10.49
N$45  (via drill 1.1 pad 1.93)
  other vias: 9.04,7.95
N$46  (via drill 1.1 pad 1.93)
  other vias: 9.04,5.41
N$47  (via drill 1.1 pad 1.93)
  other vias: 9.04,2.87
N$48  (via drill 1.1 pad 1.93)
  other vias: 36.98,18.11
N$49
  Bottom 0.635: 8.79,19.89 37.36,19.89
N$66  (via drill 1.1 pad 1.93)
  other vias: 14.12,18.11
N$67  (via drill 1.1 pad 1.93)
  other vias: 16.66,18.11
N$68  (via drill 1.1 pad 1.93)
  other vias: 19.2,18.11
N$69  (via drill 1.1 pad 1.93)
  other vias: 21.74,18.11
N$72  (via drill 1.1 pad 1.93)
  other vias: 29.36,18.11
N$73  (via drill 1.1 pad 1.93)
  other vias: 31.9,18.11
N$74  (via drill 1.1 pad 1.93)
  other vias: 34.44,18.11
N$76  (via drill 1.1 pad 1.93)
  other vias: 14.12,15.57
N$77  (via drill 1.1 pad 1.93)
  other vias: 16.66,15.57
N$78  (via drill 1.1 pad 1.93)
  other vias: 19.2,15.57
N$79  (via drill 1.1 pad 1.93)
  other vias: 21.74,15.57
N$80  (via drill 1.1 pad 1.93)
  other vias: 24.28,15.57
N$81  (via drill 1.1 pad 1.93)
  other vias: 26.82,15.57
N$82  (via drill 1.1 pad 1.93)
  other vias: 29.36,15.57
N$83  (via drill 1.1 pad 1.93)
  other vias: 31.9,15.57
N$84  (via drill 1.1 pad 1.93)
  other vias: 34.44,15.57
N$85  (via drill 1.1 pad 1.93)
  other vias: 36.98,15.57
N$86  (via drill 1.1 pad 1.93)
  other vias: 14.12,13.03
N$87  (via drill 1.1 pad 1.93)
  other vias: 16.66,13.03
N$88  (via drill 1.1 pad 1.93)
  other vias: 19.2,13.03
N$89  (via drill 1.1 pad 1.93)
  other vias: 21.74,13.03
N$90  (via drill 1.1 pad 1.93)
  other vias: 24.28,13.03
N$91  (via drill 1.1 pad 1.93)
  other vias: 26.82,13.03
N$92  (via drill 1.1 pad 1.93)
  other vias: 29.36,13.03
N$93  (via drill 1.1 pad 1.93)
  other vias: 31.9,13.03
N$94  (via drill 1.1 pad 1.93)
  other vias: 34.44,13.03
N$95  (via drill 1.1 pad 1.93)
  other vias: 36.98,13.03
N$96  (via drill 1.1 pad 1.93)
  other vias: 14.12,10.49
N$98  (via drill 1.1 pad 1.93)
  other vias: 16.66,10.49
N$100  (via drill 1.1 pad 1.93)
  other vias: 21.74,10.49
N$101  (via drill 1.1 pad 1.93)
  other vias: 24.28,10.49
N$102  (via drill 1.1 pad 1.93)
  other vias: 26.82,10.49
N$103  (via drill 1.1 pad 1.93)
  other vias: 29.36,10.49
N$104  (via drill 1.1 pad 1.93)
  other vias: 31.9,10.49
N$105  (via drill 1.1 pad 1.93)
  other vias: 34.44,10.49
N$106  (via drill 1.1 pad 1.93)
  other vias: 36.98,10.49
N$107  (via drill 1.1 pad 1.93)
  other vias: 14.12,7.95
N$108  (via drill 1.1 pad 1.93)
  other vias: 16.66,7.95
N$109  (via drill 1.1 pad 1.93)
  other vias: 19.2,7.95
N$110  (via drill 1.1 pad 1.93)
  other vias: 21.74,7.95
N$111  (via drill 1.1 pad 1.93)
  other vias: 24.28,7.95
N$112  (via drill 1.1 pad 1.93)
  other vias: 26.82,7.95
N$113  (via drill 1.1 pad 1.93)
  other vias: 29.36,7.95
N$114  (via drill 1.1 pad 1.93)
  other vias: 31.9,7.95
N$115  (via drill 1.1 pad 1.93)
  other vias: 34.44,7.95
N$116  (via drill 1.1 pad 1.93)
  other vias: 36.98,7.95
N$117  (via drill 1.1 pad 1.93)
  other vias: 14.12,5.41
N$118  (via drill 1.1 pad 1.93)
  other vias: 16.66,5.41
N$119  (via drill 1.1 pad 1.93)
  other vias: 19.2,5.41
N$120  (via drill 1.1 pad 1.93)
  other vias: 21.74,5.41
N$121  (via drill 1.1 pad 1.93)
  other vias: 24.28,5.41
N$122  (via drill 1.1 pad 1.93)
  other vias: 26.82,5.41
N$123  (via drill 1.1 pad 1.93)
  other vias: 29.36,5.41
N$124  (via drill 1.1 pad 1.93)
  other vias: 31.9,5.41
N$125  (via drill 1.1 pad 1.93)
  other vias: 34.44,5.41
N$126  (via drill 1.1 pad 1.93)
  other vias: 36.98,5.41
N$127  (via drill 1.1 pad 1.93)
  other vias: 14.12,2.87
N$128  (via drill 1.1 pad 1.93)
  other vias: 16.66,2.87
N$129  (via drill 1.1 pad 1.93)
  other vias: 19.2,2.87
N$130  (via drill 1.1 pad 1.93)
  other vias: 21.74,2.87
N$131  (via drill 1.1 pad 1.93)
  other vias: 24.28,2.87
N$132  (via drill 1.1 pad 1.93)
  other vias: 26.82,2.87
N$133  (via drill 1.1 pad 1.93)
  other vias: 29.36,2.87
N$134  (via drill 1.1 pad 1.93)
  other vias: 31.9,2.87
N$135  (via drill 1.1 pad 1.93)
  other vias: 34.44,2.87
N$136  (via drill 1.1 pad 1.93)
  other vias: 36.98,2.87
OLED_CS
  Top 0.279: 36.73,36.53 36.73,39.32 35.46,40.59 35.46,49.48 32.28,49.48 31.65,50.11 31.65,52.02 J1.P1_24
  Top 0.305: 36.73,36.53 36.73,29.29 34.82,27.38 25.93,27.38 J3.4 21.8,23.13 J4.4
  Bottom 0.305: J3.4 18.57,26.37 16.15,26.37 12.6,29.92 J2.5
OLED_DC
  Top 0.305: J2.16 40.54,30.68 35.96,26.11 29.74,26.11 J3.6 26.8,23.17 J4.6
  Bottom 0.279: J1.P1_22 29.11,52.02 29.11,45.67 34.57,45.67 40.54,39.7 J2.16
OLED_RST
  Top 0.305: J2.15 38,29.29 35.46,26.75 27.84,26.75 J3.5 24.3,23.17 J4.5
  Bottom 0.279: J1.P1_18 24.03,52.02 24.03,46.81 25.68,45.16 34.19,45.16 38,41.35 J2.15
PIEZO  (via drill 0.51)
  Top 0.279: J1.P1_12 15.9,53.29 17.17,52.02 18.13,52.02 18.95,51.21 18.95,50.24 19.96,49.1 26.31,49.1 26.31,48.46 26.57,48.21 26.57,40.59 29.11,40.59 29.11,39.19 J2.12 | v37.23,40.72 38.5,40.72 39.27,39.95 39.27,30.68 v38.76,30.18
  Bottom 0.279: J2.12 30.38,40.08 32.28,41.99 36.47,41.99 37.23,41.22 v37.23,40.72
  Bottom 0.305: v38.76,30.18 38.5,29.92 38.5,22.3 38.25,22.05 38.25,14.81 38.76,14.3 40.92,14.3 41.93,13.28 41.93,9.6 41.93,9.47 42.48,8.93 SG1.P$1
ROT_A  (via drill 0.5, 0.51)
  Top 0.279: v11.33,39.57 11.83,40.08 11.83,40.59 13.87,40.59 13.87,48.21 11.33,48.21 11.33,45.67 9.29,47.7 9.29,47.96 11.33,49.99 11.33,52.4 10.44,53.29 J1.P1_8
  Top 0.305: v10.06,26.11 10.06,28.14 v10.95,29.03
  Bottom 0.279: J2.9 20.85,40.08 11.83,40.08 v11.33,39.57 11.33,36.4 10.95,36.02 v10.95,29.03
  Bottom 0.305: J7.2 4.48,18 10.06,23.57 v10.06,26.11
ROT_B  (via drill 0.51)
  Top 0.279: J1.P1_10 13.36,53.29 14.63,52.02 15.64,52.02 16.41,51.26 16.41,49.99 18.18,48.21 16.41,48.21 16.41,45.67 18.95,45.67 18.95,40.59 20.98,40.59 20.98,40.08 21.49,39.57 21.49,36.14 21.61,36.02 v21.49,36.02 25.17,36.02 25.3,36.14 J2.10
  Top 0.305: v11.2,26.11 11.96,25.35 20.09,25.35 22.76,28.02 v22.76,29.29
  Bottom 0.305: v22.76,29.29 22.76,35.64 21.87,35.64 arc-90 v21.49,36.02 | J7.1 3.37,16 11.2,23.83 v11.2,26.11
ROT_SW  (via drill 0.51, 0.61)
  Top 0.254: v8.79,29.29 v8.79,26.11
  Top 0.279: 14.5,50.75 12.6,48.84 14.5,48.84 14.5,47.57 14.76,47.57 v15.39,48.21
  Bottom 0.254: J2.11 27.84,40.08 23.39,44.53 19.07,44.53 v15.39,48.21 8.79,41.61 v8.79,29.29
  Bottom 0.279: v15.39,48.21 15.39,50.37 J1.P1_11
  Bottom 0.305: J7.3 5.21,20 8.79,23.57 v8.79,26.11
SD_CS  (via drill 0.51)
  Top 0.279: J3.3 24.66,28.65 v32.92,28.65
  Top 0.305: J4.3 19.3,23.09 J3.3
  Bottom 0.279: J1.P1_26 32.92,52.53 31.65,51.26 31.65,49.48 41.68,39.45 41.68,36.14 39.27,33.73 37.36,33.73
  Bottom 0.305: J2.4 10.06,28.78 10.56,28.27 13.36,28.27 16.15,25.48 16.91,25.48 J3.3 | v32.92,28.65 34.19,29.92 34.19,33.1 34.82,33.73 37.36,33.73
SHUTDOWN  (via drill 0.51)
  Top 0.279: J1.P1_7 10.06,49.48 8.79,48.21 6.25,48.21 6.25,40.59 8.79,40.59 8.79,43.13 11.33,40.59 9.93,40.59 J2.3
  Top 0.305: v34.95,32.08 10.44,32.08 7.01,35.51 7.01,37.67 J2.3 | v61.75,28.52 v61.75,25.1
  Bottom 0.305: v61.75,28.52 61.24,29.03 55.4,29.03 49.43,35 49.43,39.7 48.92,40.21 47.14,40.21 46.76,39.83 46.76,35.89 46.51,35.64 44.98,35.64 41.43,32.08 v34.95,32.08 | v61.75,25.1 65.05,25.1 67.71,27.76 67.71,29.03 67.97,29.29 SJ5.3
SPI_MISO  (via drill 0.5, 0.51)
  Top 0.279: v25.04,46.94 24.66,46.94 24.66,45.03 22.12,45.03 22.12,41.22 v22.5,41.61 | J2.6 13.23,39.83 13.23,39.95 14.5,39.95 14.5,43.89 v14.88,44.27
  Top 0.305: v20.98,28.65 v15.14,28.65 | J4.9 34.3,23.05 J3.9
  Bottom 0.279: v22.5,41.61 17.3,41.61 v14.88,44.27
  Bottom 0.305: v15.14,28.65 J2.6 | J3.9 31.52,26.11 24.66,26.11 22.12,28.65 v20.98,28.65 | v25.04,46.94 25.8,46.94 27.84,48.97 J1.P1_21
SPI_MOSI  (via drill 0.5, 0.51)
  Top 0.254: 18.31,43.13 18.31,44.02 v17.93,44.4
  Top 0.279: v25.3,48.21 25.93,47.57 25.93,40.59 25.3,40.59 v24.66,41.22 | 18.31,43.13 18.31,39.95 18.95,39.95 18.95,39.45 J2.7
  Top 0.305: v20.98,27.38 v17.68,27.38 | J4.8 31.8,23.09 J3.8
  Bottom 0.254: 22.12,43.13 19.2,43.13 v17.93,44.4
  Bottom 0.279: J1.P1_19 v25.3,48.21 | v24.66,41.22 24.03,41.22 22.12,43.13
  Bottom 0.305: J3.8 31.9,23.32 29.74,25.48 22.88,25.48 v20.98,27.38 | v17.68,27.38 J2.7
SPI_SCLK
  Top 0.279: J1.P1_23 32.28,48.84 34.82,48.84 34.82,45.03 32.28,45.03 32.28,43.76 34.82,43.76 34.82,39.95 34.19,39.95 34.19,37.03
  Top 0.305: J2.8 20.22,35.64 20.85,35 32.92,35 34.19,36.27 34.19,37.03 | J4.7 29.3,23.13 J3.7
  Bottom 0.305: J2.8 20.22,26.11 21.49,24.84 27.71,24.84 J3.7
SRN
  Top 0.254: 50.74,25.39 C12.1 50.14,25.39 49.93,25.18 49.93,24.21 49.4,23.67 U2.8
  Top 0.305: C12.1 51.71,25.39 51.84,25.52 51.84,26.75 52.09,27 52.77,27 C14.1 R19.1
SRP
  Top 0.254: C15.2 49.78,21.96 U2.7
  Top 0.305: C14.2 52.94,25.39
  Top 0.406: C14.2 52.86,25.22 52.35,24.71 52.35,21.92 | 52.35,21.92 53.2,21.92 R14.1 | 52.35,21.92 51.24,21.92 C15.2
TS  (via drill 0.51)
  Top 0.254: R28.2 66.44,52.44 | 66.44,52.44 66.06,52.44 | 66.06,52.44 R29.1 | 66.44,52.44 v66.44,54.94 65.81,55.58 52.73,55.58 arc90 52.47,55.32 52.47,43.64 51.97,43.13 51.97,33.73 51.59,33.35 v47.14,33.35 | 66.06,52.44 66.06,48.21 67.78,46.5 U3.1
  Bottom 0.254: TEMP.1 76.48,54.94 v66.44,54.94 | SJ1.1 39.9,23.19 39.14,23.95 39.14,29.16 40.41,30.43 42.19,30.43 45.11,33.35 v47.14,33.35
TS_GAUGE  (via drill 0.51)
  Top 0.305: R21.1 44.35,20.65 44.09,20.9 v42.57,20.9 42.57,22.47 R20.1
  Bottom 0.305: SJ1.2 40.79,21.79 41.68,20.9 v42.57,20.9
VBAT  (via drill 0.51, 0.58)
  Top 0.254: v64.29,29.16 64.79,29.67 64.79,36.4 64.92,36.53 64.92,37.8 67.21,40.08 67.84,40.08 68.1,40.34 68.1,42.68 66.83,43.96 v66.19,43.96 | U2.3 48.59,16.14 v48.73,16.14 48.99,16.14 U2.4
  Top 0.305: C19.1 51.29,15.32 51.97,15.32 | 51.97,15.32 53.15,15.32 C13.1 | v51.97,16.59 51.97,15.32 | U3.2 66.57,45.42 v66.19,45.03 66.32,44.91 U3.3
  Bottom 0.305: v64.29,29.16 62.51,27.38 54.13,27.38 52.35,25.6 52.35,17.86 51.97,17.48 | 51.97,17.48 48.73,17.48 v48.73,16.14 | v51.97,16.59 51.97,17.48
  Bottom 0.914: 66.19,43.89 v66.19,45.03 66.89,45.73 66.89,53.35 67.71,54.18 74.06,54.18 76.1,52.15 81.95,52.15 J8.1
  pour Top: 65.81,46.05 66.83,46.05 66.83,43.51 65.81,43.51
VBAT_NEG  (via drill 0.51)
  Top 0.813: v55.01,25.1 v55.01,24.08 56.54,24.08 | R14.2 53.45,23.66 54.25,24.46 54.63,24.46 54.63,24.59 v55.01,25.1 | 55.4,24.59 R15.1 55.88,25.1 v55.01,25.1
  Bottom 0.813: J8.2 83.61,53.91 84.1,53.42 84.1,38.81 83.72,38.43 74.95,38.43 74.19,37.67 74.19,27.76 73.43,27 68.98,27 66.06,24.08 v55.01,24.08 v55.01,25.1
VBAT_SW  (via drill 0.51, 0.58, 1.1 pad 1.93)
  Top 0.254: 72.29,33.6 Q1.5
  Top 0.305: v67.46,32.46 66.57,32.46 65.68,31.57 65.68,29.29 | 65.68,29.29 67.68,29.29 C5.1 | 65.68,28.4 R2.2 65.68,29.29 | U1.11 57.54,35.94 57.3,35.7 55.84,35.7 v55.65,35.51
  Top 0.406: U1.8 59.89,38.25
  Top 0.914: v67.46,32.46 v68.48,32.46 70.38,34.37
  Top 1.016: L1.P$2 L1.P$1 54.51,45.77
  Bottom 0.305: 63.02,34.37 63.02,34.43 56.73,34.43 v55.65,35.51
  Bottom 0.61: v39.52,15.57 46.63,15.57 48.16,14.05 53.24,14.05 53.87,14.68 53.87,25.22 54.76,26.11 64.41,26.11 66.57,28.27 66.57,32.46 67.84,32.46
  Bottom 1.016: v58.63,39.32 v58.63,38.18 62.63,38.18 63.02,37.8 63.02,34.37 63.02,34.11 64.67,32.46 66.57,32.46 v67.46,32.46 67.84,32.46 v68.48,32.46
  pour Top (no thermals): 70.38,35.13 73.05,35.13 73.05,33.6 70.38,33.6 70,33.99 70,34.75
  pour Top: 53.24,46.3 56.03,46.3 57.05,45.29 57.05,42.24 59.97,39.32 59.97,37.92 57.81,37.92 57.43,37.54 56.41,37.54 55.14,38.81 53.24,38.81

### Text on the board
bPlace: 2mm
tNames: +BAT- | CHARGE: | OK | ++ | CHARGE | + - | 5V | version one point oh | docs.nextthing.co | +Soft On/Off | +LiPo Charging & Gauge | ON/ | Call me Bob. | OFF | +LiPo 5V DC/DC Booster | * | SDA | SCK | GP04 | GP07 | GP08 | MISO | MOSI | SCLK | GP14 | GP15 | GP17 | GP18 | GP22 | GP23 | GP24 | GP25 | GP27 | GND | 3.3V | 5V | BTN | - | + | CE1 | CE0 | 24 | 25 | SCK | SI | SO | 27 | SPI | ROT | 5 | 3 | * | I²C | 5 | 3
bNames: - | DC DC | IC: BQ24075 | LiPo | IC: TPS61032 | TS | BAT | + | BQ24075 | *LiPo Charger: | BQ27510 | *LiPo Gauger: | - | TPS61032 | *LiPo Booster: | + | CHG | REALLY REALLY OPEN | IRF7319 | *Soft Powerer: | CHARGER | Next Thing Co. // OAKLAND Calif. | - | ON | + | SOFT | SDA | SCK | GP04 | GP07 | GP08 | MISO | MOSI | SCLK | GP14 | GP15 | GP17 | GP18 | GP22 | GP23 | GP24 | GP25 | GP27 | GND | 3.3V | 5V | ON/OFF | IC: IRF7319 | GND | SPI / DISPLAY | 4 | GAUGE | BATTERY | 23 | CHGR-> | ShutDowN | GND | V+ | CE1 | CE0 | 24 | 25 | SCK | SI | SO | 27 | IC: BQ27510 | FUEL------ | GND | 0.1" | E P | T M | 17 | -> | 14 | B.STAT | 15 | BAT.SW | GND | V+ | SDA | /GND | SCK | 27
